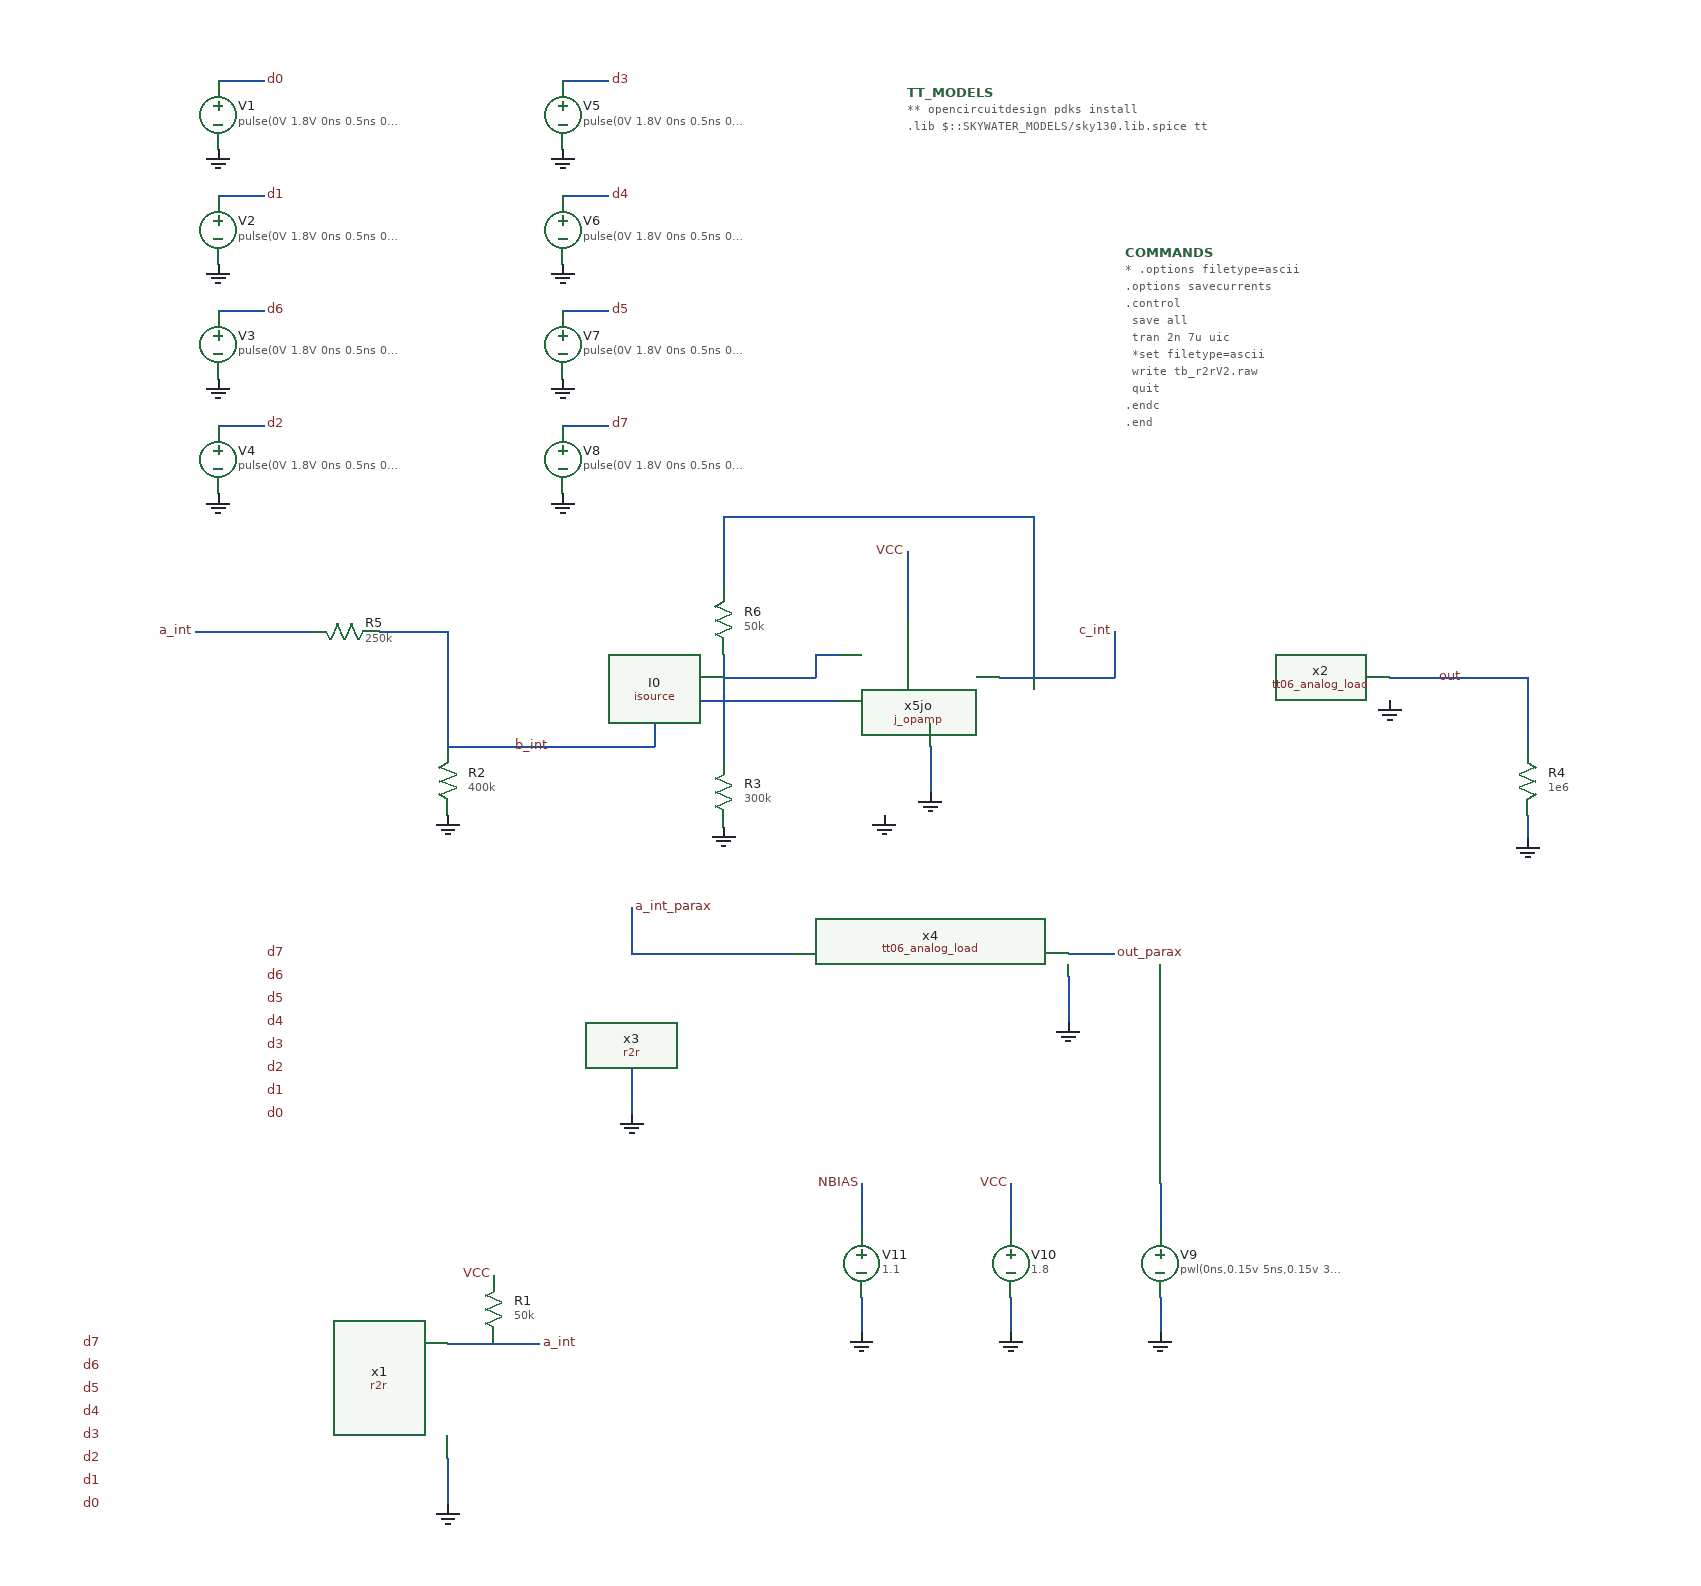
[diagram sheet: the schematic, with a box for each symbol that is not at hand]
v {xschem version=3.4.5 file_version=1.2
}
G {}
K {}
V {}
S {}
E {}
B 2 1490 -880 3030 -180 {flags=graph
y1=7.8e-05
y2=1.8
ypos1=0
ypos2=2
divy=5
subdivy=1
unity=1
x1=5e-12
x2=7e-06
divx=5
subdivx=1
xlabmag=1.0
ylabmag=1.0
node="d1
a_int
c_int
out"
color="5 21 11 6"
dataset=-1
unitx=1
logx=0
logy=0
}
B 2 1490 -1610 3030 -910 {flags=graph
y1=0
y2=0.0015
ypos1=0
ypos2=2
divy=5
subdivy=1
unity=1
x1=5e-12
x2=7e-06
divx=5
subdivx=1
xlabmag=1.0
ylabmag=1.0


dataset=-1
unitx=1
logx=0
logy=0


rainbow=1























color="8 8 8 8 8 8 12 10 11 16 7 7 7 17 17 17 17 17 17 17 17 17 17 17 17 17 17 17 17 17"
node="i(@m.x5jo.xm9.msky130_fd_pr__nfet_01v8[is])
i(@m.x5jo.xm9.msky130_fd_pr__nfet_01v8[ig])
i(@m.x5jo.xm9.msky130_fd_pr__nfet_01v8[id])
i(@m.x5jo.xm9.msky130_fd_pr__nfet_01v8[ib])
i(@m.x5jo.xm8.msky130_fd_pr__pfet_01v8[is])
i(@m.x5jo.xm8.msky130_fd_pr__pfet_01v8[ig])
i(@m.x5jo.xm8.msky130_fd_pr__pfet_01v8[id])
i(@m.x5jo.xm7.msky130_fd_pr__pfet_01v8[id])
i(@m.x5jo.xm6.msky130_fd_pr__nfet_01v8[id])
i(@m.x5jo.xm6.msky130_fd_pr__nfet_01v8[ib])
i(@m.x5jo.xm5.msky130_fd_pr__pfet_01v8[is])
i(@m.x5jo.xm5.msky130_fd_pr__pfet_01v8[ig])
i(@m.x5jo.xm5.msky130_fd_pr__pfet_01v8[id])
i(@m.x5jo.xm5.msky130_fd_pr__pfet_01v8[ib])
i(@m.x5jo.xm4.msky130_fd_pr__nfet_01v8[is])
i(@m.x5jo.xm4.msky130_fd_pr__nfet_01v8[ig])
i(@m.x5jo.xm4.msky130_fd_pr__nfet_01v8[id])
i(@m.x5jo.xm4.msky130_fd_pr__nfet_01v8[ib])
i(@m.x5jo.xm3.msky130_fd_pr__nfet_01v8[is])
i(@m.x5jo.xm3.msky130_fd_pr__nfet_01v8[ig])
i(@m.x5jo.xm3.msky130_fd_pr__nfet_01v8[id])
i(@m.x5jo.xm3.msky130_fd_pr__nfet_01v8[ib])
i(@m.x5jo.xm2.msky130_fd_pr__pfet_01v8[is])
i(@m.x5jo.xm2.msky130_fd_pr__pfet_01v8[ig])
i(@m.x5jo.xm2.msky130_fd_pr__pfet_01v8[id])
i(@m.x5jo.xm2.msky130_fd_pr__pfet_01v8[ib])
i(@m.x5jo.xm1.msky130_fd_pr__pfet_01v8[is])
i(@m.x5jo.xm1.msky130_fd_pr__pfet_01v8[ig])
i(@m.x5jo.xm1.msky130_fd_pr__pfet_01v8[id])
i(@m.x5jo.xm1.msky130_fd_pr__pfet_01v8[ib])"}
N 240 -320 240 -300 {
lab=GND}
N 240 -300 240 -280 {
lab=GND}
N 1060 -1000 1100 -1000 {
lab=out}
N 40 -1520 80 -1520 {
lab=d0}
N 40 -1420 80 -1420 {
lab=d1}
N 40 -1320 80 -1320 {
lab=d6}
N 40 -1220 80 -1220 {
lab=d2}
N 340 -1520 380 -1520 {
lab=d3}
N 340 -1420 380 -1420 {
lab=d4}
N 340 -1320 380 -1320 {
lab=d5}
N 340 -1220 380 -1220 {
lab=d7}
N 400 -660 400 -640 {
lab=GND}
N 400 -640 400 -620 {
lab=GND}
N 780 -760 820 -760 {
lab=out_parax}
N 400 -800 400 -760 {
lab=a_int_parax}
N 400 -760 420 -760 {
lab=a_int_parax}
N 420 -760 540 -760 {
lab=a_int_parax}
N 780 -740 780 -700 {
lab=GND}
N 730 -460 730 -430 {
lab=GND}
N 730 -560 730 -520 {
lab=VCC}
N 1180 -880 1180 -860 {
lab=GND}
N 1100 -1000 1180 -1000 {
lab=out}
N 1180 -1000 1180 -940 {
lab=out}
N 820 -1040 820 -1000 {
lab=c_int}
N 240 -420 320 -420 {
lab=a_int}
N 860 -460 860 -430 {
lab=GND}
N 860 -560 860 -520 {
lab=#net1}
N 20 -1040 120 -1040 {
lab=a_int}
N 600 -460 600 -430 {
lab=GND}
N 600 -560 600 -520 {
lab=NBIAS}
N 660 -940 660 -900 {
lab=GND}
N 180 -1040 240 -1040 {
lab=b_int}
N 240 -1040 240 -940 {
lab=b_int}
N 240 -940 390 -940 {
lab=b_int}
N 720 -1000 820 -1000 {
lab=c_int}
N 640 -1110 640 -1050 {
lab=VCC}
N 390 -940 420 -940 {
lab=b_int}
N 420 -980 420 -940 {
lab=b_int}
N 420 -980 580 -980 {
lab=b_int}
N 750 -1140 750 -1000 {
lab=c_int}
N 540 -1140 750 -1140 {
lab=c_int}
N 480 -1020 480 -930 {
lab=#net2}
N 480 -1140 480 -1080 {
lab=c_int}
N 480 -1140 540 -1140 {
lab=c_int}
N 480 -1000 560 -1000 {
lab=#net2}
N 560 -1020 560 -1000 {
lab=#net2}
N 560 -1020 580 -1020 {
lab=#net2}
C {devices/code.sym} 640 -1510 0 0 {name=TT_MODELS
only_toplevel=true
format="tcleval( @value )"
value="
** opencircuitdesign pdks install
.lib $::SKYWATER_MODELS/sky130.lib.spice tt

"
spice_ignore=false}
C {devices/launcher.sym} 840 -1500 0 0 {name=h17 
descr="Load waves" 
tclcommand="
xschem raw_read $netlist_dir/[file tail [file rootname [xschem get current_name]]].raw tran

"
}
C {r2r.sym} 90 -350 0 0 {name=x1}
C {devices/gnd.sym} 240 -280 0 0 {name=l1 lab=GND}
C {tt06_analog_load.sym} 910 -980 0 0 {name=x2}
C {devices/gnd.sym} 1060 -980 0 0 {name=l2 lab=GND}
C {devices/lab_pin.sym} 1100 -1000 2 0 {name=p1 sig_type=std_logic lab=out}
C {devices/vsource.sym} 40 -1490 0 0 {name=V1 value="pulse(0V 1.8V 0ns 0.5ns 0.5ns 20ns 40ns)" savecurrent=false}
C {devices/lab_pin.sym} 80 -1520 2 0 {name=p2 sig_type=std_logic lab=d0}
C {devices/gnd.sym} 40 -1460 0 0 {name=l3 lab=GND}
C {devices/vsource.sym} 40 -1390 0 0 {name=V2 value="pulse(0V 1.8V 0ns 0.5ns 0.5ns 40ns 80ns)" savecurrent=false}
C {devices/lab_pin.sym} 80 -1420 2 0 {name=p3 sig_type=std_logic lab=d1}
C {devices/gnd.sym} 40 -1360 0 0 {name=l4 lab=GND}
C {devices/vsource.sym} 40 -1290 0 0 {name=V3 value="pulse(0V 1.8V 0ns 0.5ns 0.5ns 80ns 160ns)" savecurrent=false}
C {devices/lab_pin.sym} 80 -1320 2 0 {name=p4 sig_type=std_logic lab=d6}
C {devices/gnd.sym} 40 -1260 0 0 {name=l5 lab=GND}
C {devices/vsource.sym} 40 -1190 0 0 {name=V4 value="pulse(0V 1.8V 0ns 0.5ns 0.5ns 160ns 320ns)" savecurrent=false}
C {devices/lab_pin.sym} 80 -1220 2 0 {name=p5 sig_type=std_logic lab=d2}
C {devices/gnd.sym} 40 -1160 0 0 {name=l6 lab=GND}
C {devices/vsource.sym} 340 -1490 0 0 {name=V5 value="pulse(0V 1.8V 0ns 0.5ns 0.5ns 320ns 640ns)" savecurrent=false}
C {devices/lab_pin.sym} 380 -1520 2 0 {name=p6 sig_type=std_logic lab=d3}
C {devices/gnd.sym} 340 -1460 0 0 {name=l7 lab=GND}
C {devices/vsource.sym} 340 -1390 0 0 {name=V6 value="pulse(0V 1.8V 0ns 0.5ns 0.5ns 640ns 1280ns)" savecurrent=false}
C {devices/lab_pin.sym} 380 -1420 2 0 {name=p7 sig_type=std_logic lab=d4}
C {devices/gnd.sym} 340 -1360 0 0 {name=l8 lab=GND}
C {devices/vsource.sym} 340 -1290 0 0 {name=V7 value="pulse(0V 1.8V 0ns 0.5ns 0.5ns 1280ns 2560ns)" savecurrent=false}
C {devices/lab_pin.sym} 380 -1320 2 0 {name=p8 sig_type=std_logic lab=d5}
C {devices/gnd.sym} 340 -1260 0 0 {name=l9 lab=GND}
C {devices/vsource.sym} 340 -1190 0 0 {name=V8 value="pulse(0V 1.8V 0ns 0.5ns 0.5ns 2560ns 5120ns)" savecurrent=false}
C {devices/lab_pin.sym} 380 -1220 2 0 {name=p9 sig_type=std_logic lab=d7}
C {devices/gnd.sym} 340 -1160 0 0 {name=l10 lab=GND}
C {devices/lab_pin.sym} -60 -280 0 0 {name=p10 sig_type=std_logic lab=d0}
C {devices/lab_pin.sym} -60 -300 0 0 {name=p11 sig_type=std_logic lab=d1}
C {devices/lab_pin.sym} -60 -320 0 0 {name=p12 sig_type=std_logic lab=d2}
C {devices/lab_pin.sym} -60 -340 0 0 {name=p13 sig_type=std_logic lab=d3}
C {devices/lab_pin.sym} -60 -360 0 0 {name=p14 sig_type=std_logic lab=d4}
C {devices/lab_pin.sym} -60 -380 0 0 {name=p15 sig_type=std_logic lab=d5}
C {devices/lab_pin.sym} -60 -400 0 0 {name=p16 sig_type=std_logic lab=d6}
C {devices/lab_pin.sym} -60 -420 0 0 {name=p17 sig_type=std_logic lab=d7}
C {devices/simulator_commands_shown.sym} 830 -1370 0 0 {name=COMMANDS
simulator=ngspice
only_toplevel=false 
value="
* .options filetype=ascii
.options savecurrents
.control
  save all
  tran 2n 7u uic
  *set filetype=ascii
  write tb_r2rV2.raw
  quit
.endc
.end
"}
C {r2r.sym} 250 -690 0 0 {name=x3
schematic=r2r_parax.sim
spice_sym_def="tcleval(.include [file normalize ../mag/r2r.sim.spice])"
tclcommand="textwindow          [file normalize ../mag/r2r.sim.spice]"
}
C {devices/gnd.sym} 400 -620 0 0 {name=l11 lab=GND}
C {tt06_analog_load.sym} 630 -740 0 0 {name=x4}
C {devices/lab_pin.sym} 820 -760 2 0 {name=p19 sig_type=std_logic lab=out_parax}
C {devices/lab_pin.sym} 100 -620 0 0 {name=p20 sig_type=std_logic lab=d0}
C {devices/lab_pin.sym} 100 -640 0 0 {name=p21 sig_type=std_logic lab=d1}
C {devices/lab_pin.sym} 100 -660 0 0 {name=p22 sig_type=std_logic lab=d2}
C {devices/lab_pin.sym} 100 -680 0 0 {name=p23 sig_type=std_logic lab=d3}
C {devices/lab_pin.sym} 100 -700 0 0 {name=p24 sig_type=std_logic lab=d4}
C {devices/lab_pin.sym} 100 -720 0 0 {name=p25 sig_type=std_logic lab=d5}
C {devices/lab_pin.sym} 100 -740 0 0 {name=p26 sig_type=std_logic lab=d6}
C {devices/lab_pin.sym} 100 -760 0 0 {name=p27 sig_type=std_logic lab=d7}
C {devices/lab_pin.sym} 400 -800 2 0 {name=p28 sig_type=std_logic lab=a_int_parax}
C {devices/gnd.sym} 780 -700 0 0 {name=l14 lab=GND}
C {devices/vsource.sym} 730 -490 0 0 {name=V10 value=1.8 savecurrent=false}
C {devices/gnd.sym} 730 -430 0 0 {name=l15 lab=GND}
C {devices/lab_pin.sym} 730 -560 0 0 {name=p30 sig_type=std_logic lab=VCC}
C {devices/res.sym} 1180 -910 0 0 {name=R4
value=1e6
footprint=1206
device=resistor
m=1}
C {devices/gnd.sym} 1180 -860 0 0 {name=l13 lab=GND}
C {devices/lab_pin.sym} 330 -940 3 0 {name=p32 sig_type=std_logic lab=b_int}
C {devices/vsource.sym} 860 -490 0 0 {name=V9
vlo=0
vhi=1.8
value="pwl(0ns,0.15v 5ns,0.15v 3us,0.85v 3.002us,0.15v 3.15us,0.15v 3.152us,0.85v 6us,0.15v 7us,0.15v)" savecurrent=false}
C {devices/gnd.sym} 860 -430 0 0 {name=l16 lab=GND}
C {devices/lab_pin.sym} 320 -420 0 1 {name=p33 sig_type=std_logic lab=a_int}
C {devices/lab_pin.sym} 20 -1040 1 0 {name=p34 sig_type=std_logic lab=a_int}
C {devices/res.sym} 150 -1040 1 0 {name=R5
value=250k
footprint=1206
device=resistor
m=1}
C {devices/vsource.sym} 600 -490 0 0 {name=V11 value=1.1 savecurrent=false}
C {devices/gnd.sym} 600 -430 0 0 {name=l12 lab=GND}
C {devices/lab_pin.sym} 600 -560 0 0 {name=p18 sig_type=std_logic lab=NBIAS}
C {devices/gnd.sym} 660 -900 0 0 {name=l17 lab=GND}
C {devices/lab_pin.sym} 640 -1110 0 0 {name=p29 sig_type=std_logic lab=VCC}
C {devices/res.sym} 280 -450 2 0 {name=R1
value=50k
footprint=1206
device=resistor
m=1}
C {devices/lab_pin.sym} 280 -480 0 0 {name=p31 sig_type=std_logic lab=VCC}
C {devices/res.sym} 240 -910 2 0 {name=R2
value=400k
footprint=1206
device=resistor
m=1}
C {devices/gnd.sym} 240 -880 0 0 {name=l18 lab=GND}
C {devices/lab_pin.sym} 820 -1040 0 0 {name=p35 sig_type=std_logic lab=c_int}
C {j_opamp.sym} 650 -1000 0 0 {name=x5jo}
C {devices/isource.sym} 620 -910 0 1 {name=I0 value=150u}
C {devices/gnd.sym} 620 -880 0 0 {name=l19 lab=GND}
C {devices/res.sym} 480 -900 2 0 {name=R3
value=300k
footprint=1206
device=resistor
m=1}
C {devices/gnd.sym} 480 -870 0 0 {name=l20 lab=GND}
C {devices/res.sym} 480 -1050 2 0 {name=R6
value=50k
footprint=1206
device=resistor
m=1}
